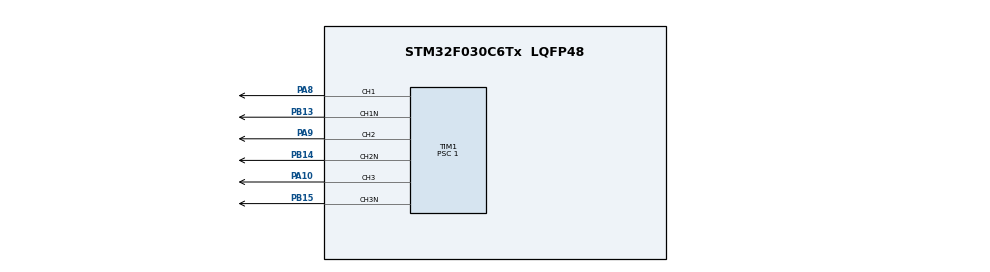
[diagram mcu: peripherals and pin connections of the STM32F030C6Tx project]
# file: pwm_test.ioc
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Mcu.Family=STM32F0
Mcu.Name=STM32F030C6Tx
Mcu.Package=LQFP48
PA10.Signal=S_TIM1_CH3
PA8.Signal=S_TIM1_CH1
PA9.Signal=S_TIM1_CH2
PB13.Mode=Output Compare1 CH1 CH1N
PB13.Signal=TIM1_CH1N
PB14.Mode=Output Compare2 CH2 CH2N
PB14.Signal=TIM1_CH2N
PB15.Mode=Output Compare3 CH3 CH3N
PB15.Signal=TIM1_CH3N
ProjectManager.HeapSize=0x200
ProjectManager.StackSize=0x400
ProjectManager.TargetToolchain=SW4STM32
SH.S_TIM1_CH1.0=TIM1_CH1,Output Compare1 CH1 CH1N
SH.S_TIM1_CH2.0=TIM1_CH2,Output Compare2 CH2 CH2N
SH.S_TIM1_CH3.0=TIM1_CH3,Output Compare3 CH3 CH3N
TIM1.Channel-Output\ Compare1\ CH1\ CH1N=TIM_CHANNEL_1
TIM1.Channel-Output\ Compare2\ CH2\ CH2N=TIM_CHANNEL_2
TIM1.Channel-Output\ Compare3\ CH3\ CH3N=TIM_CHANNEL_3
TIM1.Prescaler=1
TIM1.Pulse-Output\ Compare1\ CH1\ CH1N=2500
TIM1.Pulse-Output\ Compare2\ CH2\ CH2N=2500
TIM1.Pulse-Output\ Compare3\ CH3\ CH3N=2500
VP_TIM1_VS_ClockSourceINT.Mode=Internal
board=custom

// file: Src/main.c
/* USER CODE BEGIN Header */
/**
  ******************************************************************************
  * @file           : main.c
  * @brief          : Main program body
  ******************************************************************************
  * @attention
  *
  * <h2><center>&copy; Copyright (c) 2020 STMicroelectronics.
  * All rights reserved.</center></h2>
  *
  * This software component is licensed by ST under BSD 3-Clause license,
  * the "License"; You may not use this file except in compliance with the
  * License. You may obtain a copy of the License at:
  *                        opensource.org/licenses/BSD-3-Clause
  *
  ******************************************************************************
  */
/* USER CODE END Header */

#include "main.h"

TIM_HandleTypeDef htim1;

void SystemClock_Config(void);
static void MX_GPIO_Init(void);
static void MX_TIM1_Init(void);

/* USER CODE BEGIN 0 */

//ch1 is PA8, HS1
//ch2 is PA9, HS2
//ch3 is PA10, HS3

//ch1n is PB13, LS1
//CH2N is PB14, LS2
//CH3N is PB15, LS3

void test1(){
  HAL_TIM_PWM_Stop(&htim1,TIM_CHANNEL_1);
	HAL_GPIO_WritePin(GPIOA,GPIO_PIN_8,GPIO_PIN_RESET);
	HAL_GPIO_WritePin(GPIOA,GPIO_PIN_9,GPIO_PIN_RESET);
	HAL_GPIO_WritePin(GPIOA,GPIO_PIN_10,GPIO_PIN_RESET);

	HAL_TIMEx_PWMN_Start(&htim1,TIM_CHANNEL_1);
}

void test1_1(){
  HAL_TIM_PWM_Stop(&htim1,TIM_CHANNEL_1);
	HAL_GPIO_WritePin(GPIOA,GPIO_PIN_8,GPIO_PIN_RESET);
	HAL_GPIO_WritePin(GPIOA,GPIO_PIN_9,GPIO_PIN_RESET);
	HAL_GPIO_WritePin(GPIOA,GPIO_PIN_10,GPIO_PIN_RESET);

  __HAL_TIM_SET_COMPARE(&htim1, TIM_CHANNEL_1, 150);
	HAL_TIMEx_PWMN_Start(&htim1,TIM_CHANNEL_1);

}

void test1_2(){
  HAL_TIM_PWM_Stop(&htim1,TIM_CHANNEL_1);
	HAL_GPIO_WritePin(GPIOA,GPIO_PIN_8,GPIO_PIN_RESET);
	HAL_GPIO_WritePin(GPIOA,GPIO_PIN_9,GPIO_PIN_RESET);
	HAL_GPIO_WritePin(GPIOA,GPIO_PIN_10,GPIO_PIN_RESET);

	HAL_TIMEx_PWMN_Start(&htim1,TIM_CHANNEL_1);
  __HAL_TIM_SET_COMPARE(&htim1, TIM_CHANNEL_1, 150);

}

//HAL_TIMEx_PWMN_Start(&htim1,TIM_CHANNEL_1);//should 1N
void test2(){
  HAL_TIMEx_PWMN_Stop(&htim1,TIM_CHANNEL_1);
	HAL_GPIO_WritePin(GPIOB,GPIO_PIN_13,GPIO_PIN_RESET);
	HAL_GPIO_WritePin(GPIOB,GPIO_PIN_14,GPIO_PIN_RESET);
	HAL_GPIO_WritePin(GPIOB,GPIO_PIN_15,GPIO_PIN_RESET);

	HAL_TIM_PWM_Start(&htim1,TIM_CHANNEL_1);
}

/* USER CODE END 0 */

int main(void)
{

  /* MCU Configuration--------------------------------------------------------*/

  /* Reset of all peripherals, Initializes the Flash interface and the Systick. */
  HAL_Init();

  /* Configure the system clock */
  SystemClock_Config();

  /* Initialize all configured peripherals */
  MX_GPIO_Init();
  MX_TIM1_Init();

  /* Infinite loop */
  while (1)
  {

  }
}

void SystemClock_Config(void)
{
  RCC_OscInitTypeDef RCC_OscInitStruct = {0};
  RCC_ClkInitTypeDef RCC_ClkInitStruct = {0};

  /** Initializes the CPU, AHB and APB busses clocks
  */
  RCC_OscInitStruct.OscillatorType = RCC_OSCILLATORTYPE_HSI;
  RCC_OscInitStruct.HSIState = RCC_HSI_ON;
  RCC_OscInitStruct.HSICalibrationValue = RCC_HSICALIBRATION_DEFAULT;
  RCC_OscInitStruct.PLL.PLLState = RCC_PLL_NONE;
  if (HAL_RCC_OscConfig(&RCC_OscInitStruct) != HAL_OK)
  {
    Error_Handler();
  }
  /** Initializes the CPU, AHB and APB busses clocks
  */
  RCC_ClkInitStruct.ClockType = RCC_CLOCKTYPE_HCLK|RCC_CLOCKTYPE_SYSCLK
                              |RCC_CLOCKTYPE_PCLK1;
  RCC_ClkInitStruct.SYSCLKSource = RCC_SYSCLKSOURCE_HSI;
  RCC_ClkInitStruct.AHBCLKDivider = RCC_SYSCLK_DIV1;
  RCC_ClkInitStruct.APB1CLKDivider = RCC_HCLK_DIV16;

  if (HAL_RCC_ClockConfig(&RCC_ClkInitStruct, FLASH_LATENCY_0) != HAL_OK)
  {
    Error_Handler();
  }
}

static void MX_TIM1_Init(void)
{

  TIM_ClockConfigTypeDef sClockSourceConfig = {0};
  TIM_MasterConfigTypeDef sMasterConfig = {0};
  TIM_OC_InitTypeDef sConfigOC = {0};
  TIM_BreakDeadTimeConfigTypeDef sBreakDeadTimeConfig = {0};

  htim1.Instance = TIM1;
  htim1.Init.Prescaler = 0;
  htim1.Init.CounterMode = TIM_COUNTERMODE_UP;
  htim1.Init.Period = 3000;
  htim1.Init.ClockDivision = TIM_CLOCKDIVISION_DIV1;
  htim1.Init.RepetitionCounter = 0;
  htim1.Init.AutoReloadPreload = TIM_AUTORELOAD_PRELOAD_DISABLE;
  if (HAL_TIM_Base_Init(&htim1) != HAL_OK)
  {
    Error_Handler();
  }
  sClockSourceConfig.ClockSource = TIM_CLOCKSOURCE_INTERNAL;
  if (HAL_TIM_ConfigClockSource(&htim1, &sClockSourceConfig) != HAL_OK)
  {
    Error_Handler();
  }
  if (HAL_TIM_PWM_Init(&htim1) != HAL_OK)
  {
    Error_Handler();
  }
  sMasterConfig.MasterOutputTrigger = TIM_TRGO_RESET;
  sMasterConfig.MasterSlaveMode = TIM_MASTERSLAVEMODE_DISABLE;
  if (HAL_TIMEx_MasterConfigSynchronization(&htim1, &sMasterConfig) != HAL_OK)
  {
    Error_Handler();
  }
  sConfigOC.OCMode = TIM_OCMODE_PWM1;
  sConfigOC.Pulse = 1500;
  sConfigOC.OCPolarity = TIM_OCPOLARITY_HIGH;
  sConfigOC.OCNPolarity = TIM_OCNPOLARITY_HIGH;
  sConfigOC.OCFastMode = TIM_OCFAST_DISABLE;
  sConfigOC.OCIdleState = TIM_OCIDLESTATE_RESET;
  sConfigOC.OCNIdleState = TIM_OCNIDLESTATE_RESET;
  if (HAL_TIM_PWM_ConfigChannel(&htim1, &sConfigOC, TIM_CHANNEL_1) != HAL_OK)
  {
    Error_Handler();
  }
  if (HAL_TIM_PWM_ConfigChannel(&htim1, &sConfigOC, TIM_CHANNEL_2) != HAL_OK)
  {
    Error_Handler();
  }
  if (HAL_TIM_PWM_ConfigChannel(&htim1, &sConfigOC, TIM_CHANNEL_3) != HAL_OK)
  {
    Error_Handler();
  }
  sBreakDeadTimeConfig.OffStateRunMode = TIM_OSSR_DISABLE;
  sBreakDeadTimeConfig.OffStateIDLEMode = TIM_OSSI_DISABLE;
  sBreakDeadTimeConfig.LockLevel = TIM_LOCKLEVEL_OFF;
  sBreakDeadTimeConfig.DeadTime = 0;
  sBreakDeadTimeConfig.BreakState = TIM_BREAK_DISABLE;
  sBreakDeadTimeConfig.BreakPolarity = TIM_BREAKPOLARITY_HIGH;
  sBreakDeadTimeConfig.AutomaticOutput = TIM_AUTOMATICOUTPUT_DISABLE;
  if (HAL_TIMEx_ConfigBreakDeadTime(&htim1, &sBreakDeadTimeConfig) != HAL_OK)
  {
    Error_Handler();
  }
  HAL_TIM_MspPostInit(&htim1);

}

static void MX_GPIO_Init(void)
{
  GPIO_InitTypeDef GPIO_InitStruct = {0};

  /* GPIO Ports Clock Enable */
  __HAL_RCC_GPIOB_CLK_ENABLE();
  __HAL_RCC_GPIOA_CLK_ENABLE();
  __HAL_RCC_GPIOF_CLK_ENABLE();

  /*Configure GPIO pin Output Level */
  HAL_GPIO_WritePin(GPIOF, GPIO_PIN_6|GPIO_PIN_7, GPIO_PIN_SET);

  /*Configure GPIO pins : PF6 PF7 */
  GPIO_InitStruct.Pin = GPIO_PIN_6|GPIO_PIN_7;
  GPIO_InitStruct.Mode = GPIO_MODE_OUTPUT_PP;
  GPIO_InitStruct.Pull = GPIO_NOPULL;
  GPIO_InitStruct.Speed = GPIO_SPEED_FREQ_LOW;
  HAL_GPIO_Init(GPIOF, &GPIO_InitStruct);

}

void Error_Handler(void)
{
}

/************************ (C) COPYRIGHT STMicroelectronics *****END OF FILE****/
